# OpenTallas memory compiler (tools/mem_compiler), ASAP7 abstract view
VERSION 5.7 ;
BUSBITCHARS "[]" ;
DIVIDERCHAR "/" ;
PROPERTYDEFINITIONS
  MACRO width INTEGER ;
  MACRO depth INTEGER ;
  MACRO banks INTEGER ;
END PROPERTYDEFINITIONS
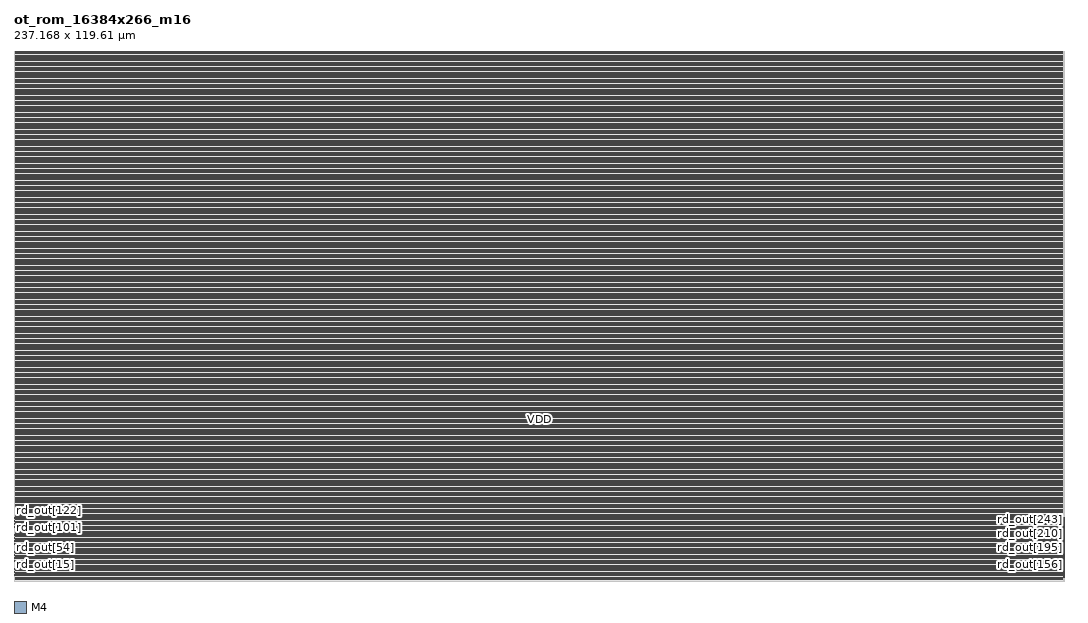
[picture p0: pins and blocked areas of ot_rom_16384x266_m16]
MACRO ot_rom_16384x266_m16
  PROPERTY width 266 ;
  PROPERTY depth 16384 ;
  PROPERTY banks 1 ;
  FOREIGN ot_rom_16384x266_m16 0 0 ;
  SYMMETRY X Y R90 ;
  SIZE 237.168 BY 119.610 ;
  CLASS BLOCK ;
  PIN clk
    DIRECTION INPUT ;
    USE CLOCK ;
    SHAPE ABUTMENT ;
    PORT
      LAYER M4 ;
      RECT 0.000 0.768 0.024 0.792 ;
    END
  END clk
  PIN ce_in
    DIRECTION INPUT ;
    USE SIGNAL ;
    SHAPE ABUTMENT ;
    PORT
      LAYER M4 ;
      RECT 0.000 0.864 0.024 0.888 ;
    END
  END ce_in
  PIN addr_in[0]
    DIRECTION INPUT ;
    USE SIGNAL ;
    SHAPE ABUTMENT ;
    PORT
      LAYER M4 ;
      RECT 0.000 0.960 0.024 0.984 ;
    END
  END addr_in[0]
  PIN addr_in[1]
    DIRECTION INPUT ;
    USE SIGNAL ;
    SHAPE ABUTMENT ;
    PORT
      LAYER M4 ;
      RECT 0.000 1.056 0.024 1.080 ;
    END
  END addr_in[1]
  PIN addr_in[2]
    DIRECTION INPUT ;
    USE SIGNAL ;
    SHAPE ABUTMENT ;
    PORT
      LAYER M4 ;
      RECT 0.000 1.152 0.024 1.176 ;
    END
  END addr_in[2]
  PIN addr_in[3]
    DIRECTION INPUT ;
    USE SIGNAL ;
    SHAPE ABUTMENT ;
    PORT
      LAYER M4 ;
      RECT 0.000 1.248 0.024 1.272 ;
    END
  END addr_in[3]
  PIN addr_in[4]
    DIRECTION INPUT ;
    USE SIGNAL ;
    SHAPE ABUTMENT ;
    PORT
      LAYER M4 ;
      RECT 0.000 1.344 0.024 1.368 ;
    END
  END addr_in[4]
  PIN addr_in[5]
    DIRECTION INPUT ;
    USE SIGNAL ;
    SHAPE ABUTMENT ;
    PORT
      LAYER M4 ;
      RECT 0.000 1.440 0.024 1.464 ;
    END
  END addr_in[5]
  PIN addr_in[6]
    DIRECTION INPUT ;
    USE SIGNAL ;
    SHAPE ABUTMENT ;
    PORT
      LAYER M4 ;
      RECT 0.000 1.536 0.024 1.560 ;
    END
  END addr_in[6]
  PIN addr_in[7]
    DIRECTION INPUT ;
    USE SIGNAL ;
    SHAPE ABUTMENT ;
    PORT
      LAYER M4 ;
      RECT 0.000 1.632 0.024 1.656 ;
    END
  END addr_in[7]
  PIN addr_in[8]
    DIRECTION INPUT ;
    USE SIGNAL ;
    SHAPE ABUTMENT ;
    PORT
      LAYER M4 ;
      RECT 0.000 1.728 0.024 1.752 ;
    END
  END addr_in[8]
  PIN addr_in[9]
    DIRECTION INPUT ;
    USE SIGNAL ;
    SHAPE ABUTMENT ;
    PORT
      LAYER M4 ;
      RECT 0.000 1.824 0.024 1.848 ;
    END
  END addr_in[9]
  PIN addr_in[10]
    DIRECTION INPUT ;
    USE SIGNAL ;
    SHAPE ABUTMENT ;
    PORT
      LAYER M4 ;
      RECT 0.000 1.920 0.024 1.944 ;
    END
  END addr_in[10]
  PIN addr_in[11]
    DIRECTION INPUT ;
    USE SIGNAL ;
    SHAPE ABUTMENT ;
    PORT
      LAYER M4 ;
      RECT 0.000 2.016 0.024 2.040 ;
    END
  END addr_in[11]
  PIN addr_in[12]
    DIRECTION INPUT ;
    USE SIGNAL ;
    SHAPE ABUTMENT ;
    PORT
      LAYER M4 ;
      RECT 0.000 2.112 0.024 2.136 ;
    END
  END addr_in[12]
  PIN addr_in[13]
    DIRECTION INPUT ;
    USE SIGNAL ;
    SHAPE ABUTMENT ;
    PORT
      LAYER M4 ;
      RECT 0.000 2.208 0.024 2.232 ;
    END
  END addr_in[13]
  PIN rd_out[0]
    DIRECTION OUTPUT ;
    USE SIGNAL ;
    SHAPE ABUTMENT ;
    PORT
      LAYER M4 ;
      RECT 0.000 2.304 0.024 2.328 ;
    END
  END rd_out[0]
  PIN rd_out[1]
    DIRECTION OUTPUT ;
    USE SIGNAL ;
    SHAPE ABUTMENT ;
    PORT
      LAYER M4 ;
      RECT 0.000 2.400 0.024 2.424 ;
    END
  END rd_out[1]
  PIN rd_out[2]
    DIRECTION OUTPUT ;
    USE SIGNAL ;
    SHAPE ABUTMENT ;
    PORT
      LAYER M4 ;
      RECT 0.000 2.496 0.024 2.520 ;
    END
  END rd_out[2]
  PIN rd_out[3]
    DIRECTION OUTPUT ;
    USE SIGNAL ;
    SHAPE ABUTMENT ;
    PORT
      LAYER M4 ;
      RECT 0.000 2.592 0.024 2.616 ;
    END
  END rd_out[3]
  PIN rd_out[4]
    DIRECTION OUTPUT ;
    USE SIGNAL ;
    SHAPE ABUTMENT ;
    PORT
      LAYER M4 ;
      RECT 0.000 2.688 0.024 2.712 ;
    END
  END rd_out[4]
  PIN rd_out[5]
    DIRECTION OUTPUT ;
    USE SIGNAL ;
    SHAPE ABUTMENT ;
    PORT
      LAYER M4 ;
      RECT 0.000 2.784 0.024 2.808 ;
    END
  END rd_out[5]
  PIN rd_out[6]
    DIRECTION OUTPUT ;
    USE SIGNAL ;
    SHAPE ABUTMENT ;
    PORT
      LAYER M4 ;
      RECT 0.000 2.880 0.024 2.904 ;
    END
  END rd_out[6]
  PIN rd_out[7]
    DIRECTION OUTPUT ;
    USE SIGNAL ;
    SHAPE ABUTMENT ;
    PORT
      LAYER M4 ;
      RECT 0.000 2.976 0.024 3.000 ;
    END
  END rd_out[7]
  PIN rd_out[8]
    DIRECTION OUTPUT ;
    USE SIGNAL ;
    SHAPE ABUTMENT ;
    PORT
      LAYER M4 ;
      RECT 0.000 3.072 0.024 3.096 ;
    END
  END rd_out[8]
  PIN rd_out[9]
    DIRECTION OUTPUT ;
    USE SIGNAL ;
    SHAPE ABUTMENT ;
    PORT
      LAYER M4 ;
      RECT 0.000 3.168 0.024 3.192 ;
    END
  END rd_out[9]
  PIN rd_out[10]
    DIRECTION OUTPUT ;
    USE SIGNAL ;
    SHAPE ABUTMENT ;
    PORT
      LAYER M4 ;
      RECT 0.000 3.264 0.024 3.288 ;
    END
  END rd_out[10]
  PIN rd_out[11]
    DIRECTION OUTPUT ;
    USE SIGNAL ;
    SHAPE ABUTMENT ;
    PORT
      LAYER M4 ;
      RECT 0.000 3.360 0.024 3.384 ;
    END
  END rd_out[11]
  PIN rd_out[12]
    DIRECTION OUTPUT ;
    USE SIGNAL ;
    SHAPE ABUTMENT ;
    PORT
      LAYER M4 ;
      RECT 0.000 3.456 0.024 3.480 ;
    END
  END rd_out[12]
  PIN rd_out[13]
    DIRECTION OUTPUT ;
    USE SIGNAL ;
    SHAPE ABUTMENT ;
    PORT
      LAYER M4 ;
      RECT 0.000 3.552 0.024 3.576 ;
    END
  END rd_out[13]
  PIN rd_out[14]
    DIRECTION OUTPUT ;
    USE SIGNAL ;
    SHAPE ABUTMENT ;
    PORT
      LAYER M4 ;
      RECT 0.000 3.648 0.024 3.672 ;
    END
  END rd_out[14]
  PIN rd_out[15]
    DIRECTION OUTPUT ;
    USE SIGNAL ;
    SHAPE ABUTMENT ;
    PORT
      LAYER M4 ;
      RECT 0.000 3.744 0.024 3.768 ;
    END
  END rd_out[15]
  PIN rd_out[16]
    DIRECTION OUTPUT ;
    USE SIGNAL ;
    SHAPE ABUTMENT ;
    PORT
      LAYER M4 ;
      RECT 0.000 3.840 0.024 3.864 ;
    END
  END rd_out[16]
  PIN rd_out[17]
    DIRECTION OUTPUT ;
    USE SIGNAL ;
    SHAPE ABUTMENT ;
    PORT
      LAYER M4 ;
      RECT 0.000 3.936 0.024 3.960 ;
    END
  END rd_out[17]
  PIN rd_out[18]
    DIRECTION OUTPUT ;
    USE SIGNAL ;
    SHAPE ABUTMENT ;
    PORT
      LAYER M4 ;
      RECT 0.000 4.032 0.024 4.056 ;
    END
  END rd_out[18]
  PIN rd_out[19]
    DIRECTION OUTPUT ;
    USE SIGNAL ;
    SHAPE ABUTMENT ;
    PORT
      LAYER M4 ;
      RECT 0.000 4.128 0.024 4.152 ;
    END
  END rd_out[19]
  PIN rd_out[20]
    DIRECTION OUTPUT ;
    USE SIGNAL ;
    SHAPE ABUTMENT ;
    PORT
      LAYER M4 ;
      RECT 0.000 4.224 0.024 4.248 ;
    END
  END rd_out[20]
  PIN rd_out[21]
    DIRECTION OUTPUT ;
    USE SIGNAL ;
    SHAPE ABUTMENT ;
    PORT
      LAYER M4 ;
      RECT 0.000 4.320 0.024 4.344 ;
    END
  END rd_out[21]
  PIN rd_out[22]
    DIRECTION OUTPUT ;
    USE SIGNAL ;
    SHAPE ABUTMENT ;
    PORT
      LAYER M4 ;
      RECT 0.000 4.416 0.024 4.440 ;
    END
  END rd_out[22]
  PIN rd_out[23]
    DIRECTION OUTPUT ;
    USE SIGNAL ;
    SHAPE ABUTMENT ;
    PORT
      LAYER M4 ;
      RECT 0.000 4.512 0.024 4.536 ;
    END
  END rd_out[23]
  PIN rd_out[24]
    DIRECTION OUTPUT ;
    USE SIGNAL ;
    SHAPE ABUTMENT ;
    PORT
      LAYER M4 ;
      RECT 0.000 4.608 0.024 4.632 ;
    END
  END rd_out[24]
  PIN rd_out[25]
    DIRECTION OUTPUT ;
    USE SIGNAL ;
    SHAPE ABUTMENT ;
    PORT
      LAYER M4 ;
      RECT 0.000 4.704 0.024 4.728 ;
    END
  END rd_out[25]
  PIN rd_out[26]
    DIRECTION OUTPUT ;
    USE SIGNAL ;
    SHAPE ABUTMENT ;
    PORT
      LAYER M4 ;
      RECT 0.000 4.800 0.024 4.824 ;
    END
  END rd_out[26]
  PIN rd_out[27]
    DIRECTION OUTPUT ;
    USE SIGNAL ;
    SHAPE ABUTMENT ;
    PORT
      LAYER M4 ;
      RECT 0.000 4.896 0.024 4.920 ;
    END
  END rd_out[27]
  PIN rd_out[28]
    DIRECTION OUTPUT ;
    USE SIGNAL ;
    SHAPE ABUTMENT ;
    PORT
      LAYER M4 ;
      RECT 0.000 4.992 0.024 5.016 ;
    END
  END rd_out[28]
  PIN rd_out[29]
    DIRECTION OUTPUT ;
    USE SIGNAL ;
    SHAPE ABUTMENT ;
    PORT
      LAYER M4 ;
      RECT 0.000 5.088 0.024 5.112 ;
    END
  END rd_out[29]
  PIN rd_out[30]
    DIRECTION OUTPUT ;
    USE SIGNAL ;
    SHAPE ABUTMENT ;
    PORT
      LAYER M4 ;
      RECT 0.000 5.184 0.024 5.208 ;
    END
  END rd_out[30]
  PIN rd_out[31]
    DIRECTION OUTPUT ;
    USE SIGNAL ;
    SHAPE ABUTMENT ;
    PORT
      LAYER M4 ;
      RECT 0.000 5.280 0.024 5.304 ;
    END
  END rd_out[31]
  PIN rd_out[32]
    DIRECTION OUTPUT ;
    USE SIGNAL ;
    SHAPE ABUTMENT ;
    PORT
      LAYER M4 ;
      RECT 0.000 5.376 0.024 5.400 ;
    END
  END rd_out[32]
  PIN rd_out[33]
    DIRECTION OUTPUT ;
    USE SIGNAL ;
    SHAPE ABUTMENT ;
    PORT
      LAYER M4 ;
      RECT 0.000 5.472 0.024 5.496 ;
    END
  END rd_out[33]
  PIN rd_out[34]
    DIRECTION OUTPUT ;
    USE SIGNAL ;
    SHAPE ABUTMENT ;
    PORT
      LAYER M4 ;
      RECT 0.000 5.568 0.024 5.592 ;
    END
  END rd_out[34]
  PIN rd_out[35]
    DIRECTION OUTPUT ;
    USE SIGNAL ;
    SHAPE ABUTMENT ;
    PORT
      LAYER M4 ;
      RECT 0.000 5.664 0.024 5.688 ;
    END
  END rd_out[35]
  PIN rd_out[36]
    DIRECTION OUTPUT ;
    USE SIGNAL ;
    SHAPE ABUTMENT ;
    PORT
      LAYER M4 ;
      RECT 0.000 5.760 0.024 5.784 ;
    END
  END rd_out[36]
  PIN rd_out[37]
    DIRECTION OUTPUT ;
    USE SIGNAL ;
    SHAPE ABUTMENT ;
    PORT
      LAYER M4 ;
      RECT 0.000 5.856 0.024 5.880 ;
    END
  END rd_out[37]
  PIN rd_out[38]
    DIRECTION OUTPUT ;
    USE SIGNAL ;
    SHAPE ABUTMENT ;
    PORT
      LAYER M4 ;
      RECT 0.000 5.952 0.024 5.976 ;
    END
  END rd_out[38]
  PIN rd_out[39]
    DIRECTION OUTPUT ;
    USE SIGNAL ;
    SHAPE ABUTMENT ;
    PORT
      LAYER M4 ;
      RECT 0.000 6.048 0.024 6.072 ;
    END
  END rd_out[39]
  PIN rd_out[40]
    DIRECTION OUTPUT ;
    USE SIGNAL ;
    SHAPE ABUTMENT ;
    PORT
      LAYER M4 ;
      RECT 0.000 6.144 0.024 6.168 ;
    END
  END rd_out[40]
  PIN rd_out[41]
    DIRECTION OUTPUT ;
    USE SIGNAL ;
    SHAPE ABUTMENT ;
    PORT
      LAYER M4 ;
      RECT 0.000 6.240 0.024 6.264 ;
    END
  END rd_out[41]
  PIN rd_out[42]
    DIRECTION OUTPUT ;
    USE SIGNAL ;
    SHAPE ABUTMENT ;
    PORT
      LAYER M4 ;
      RECT 0.000 6.336 0.024 6.360 ;
    END
  END rd_out[42]
  PIN rd_out[43]
    DIRECTION OUTPUT ;
    USE SIGNAL ;
    SHAPE ABUTMENT ;
    PORT
      LAYER M4 ;
      RECT 0.000 6.432 0.024 6.456 ;
    END
  END rd_out[43]
  PIN rd_out[44]
    DIRECTION OUTPUT ;
    USE SIGNAL ;
    SHAPE ABUTMENT ;
    PORT
      LAYER M4 ;
      RECT 0.000 6.528 0.024 6.552 ;
    END
  END rd_out[44]
  PIN rd_out[45]
    DIRECTION OUTPUT ;
    USE SIGNAL ;
    SHAPE ABUTMENT ;
    PORT
      LAYER M4 ;
      RECT 0.000 6.624 0.024 6.648 ;
    END
  END rd_out[45]
  PIN rd_out[46]
    DIRECTION OUTPUT ;
    USE SIGNAL ;
    SHAPE ABUTMENT ;
    PORT
      LAYER M4 ;
      RECT 0.000 6.720 0.024 6.744 ;
    END
  END rd_out[46]
  PIN rd_out[47]
    DIRECTION OUTPUT ;
    USE SIGNAL ;
    SHAPE ABUTMENT ;
    PORT
      LAYER M4 ;
      RECT 0.000 6.816 0.024 6.840 ;
    END
  END rd_out[47]
  PIN rd_out[48]
    DIRECTION OUTPUT ;
    USE SIGNAL ;
    SHAPE ABUTMENT ;
    PORT
      LAYER M4 ;
      RECT 0.000 6.912 0.024 6.936 ;
    END
  END rd_out[48]
  PIN rd_out[49]
    DIRECTION OUTPUT ;
    USE SIGNAL ;
    SHAPE ABUTMENT ;
    PORT
      LAYER M4 ;
      RECT 0.000 7.008 0.024 7.032 ;
    END
  END rd_out[49]
  PIN rd_out[50]
    DIRECTION OUTPUT ;
    USE SIGNAL ;
    SHAPE ABUTMENT ;
    PORT
      LAYER M4 ;
      RECT 0.000 7.104 0.024 7.128 ;
    END
  END rd_out[50]
  PIN rd_out[51]
    DIRECTION OUTPUT ;
    USE SIGNAL ;
    SHAPE ABUTMENT ;
    PORT
      LAYER M4 ;
      RECT 0.000 7.200 0.024 7.224 ;
    END
  END rd_out[51]
  PIN rd_out[52]
    DIRECTION OUTPUT ;
    USE SIGNAL ;
    SHAPE ABUTMENT ;
    PORT
      LAYER M4 ;
      RECT 0.000 7.296 0.024 7.320 ;
    END
  END rd_out[52]
  PIN rd_out[53]
    DIRECTION OUTPUT ;
    USE SIGNAL ;
    SHAPE ABUTMENT ;
    PORT
      LAYER M4 ;
      RECT 0.000 7.392 0.024 7.416 ;
    END
  END rd_out[53]
  PIN rd_out[54]
    DIRECTION OUTPUT ;
    USE SIGNAL ;
    SHAPE ABUTMENT ;
    PORT
      LAYER M4 ;
      RECT 0.000 7.488 0.024 7.512 ;
    END
  END rd_out[54]
  PIN rd_out[55]
    DIRECTION OUTPUT ;
    USE SIGNAL ;
    SHAPE ABUTMENT ;
    PORT
      LAYER M4 ;
      RECT 0.000 7.584 0.024 7.608 ;
    END
  END rd_out[55]
  PIN rd_out[56]
    DIRECTION OUTPUT ;
    USE SIGNAL ;
    SHAPE ABUTMENT ;
    PORT
      LAYER M4 ;
      RECT 0.000 7.680 0.024 7.704 ;
    END
  END rd_out[56]
  PIN rd_out[57]
    DIRECTION OUTPUT ;
    USE SIGNAL ;
    SHAPE ABUTMENT ;
    PORT
      LAYER M4 ;
      RECT 0.000 7.776 0.024 7.800 ;
    END
  END rd_out[57]
  PIN rd_out[58]
    DIRECTION OUTPUT ;
    USE SIGNAL ;
    SHAPE ABUTMENT ;
    PORT
      LAYER M4 ;
      RECT 0.000 7.872 0.024 7.896 ;
    END
  END rd_out[58]
  PIN rd_out[59]
    DIRECTION OUTPUT ;
    USE SIGNAL ;
    SHAPE ABUTMENT ;
    PORT
      LAYER M4 ;
      RECT 0.000 7.968 0.024 7.992 ;
    END
  END rd_out[59]
  PIN rd_out[60]
    DIRECTION OUTPUT ;
    USE SIGNAL ;
    SHAPE ABUTMENT ;
    PORT
      LAYER M4 ;
      RECT 0.000 8.064 0.024 8.088 ;
    END
  END rd_out[60]
  PIN rd_out[61]
    DIRECTION OUTPUT ;
    USE SIGNAL ;
    SHAPE ABUTMENT ;
    PORT
      LAYER M4 ;
      RECT 0.000 8.160 0.024 8.184 ;
    END
  END rd_out[61]
  PIN rd_out[62]
    DIRECTION OUTPUT ;
    USE SIGNAL ;
    SHAPE ABUTMENT ;
    PORT
      LAYER M4 ;
      RECT 0.000 8.256 0.024 8.280 ;
    END
  END rd_out[62]
  PIN rd_out[63]
    DIRECTION OUTPUT ;
    USE SIGNAL ;
    SHAPE ABUTMENT ;
    PORT
      LAYER M4 ;
      RECT 0.000 8.352 0.024 8.376 ;
    END
  END rd_out[63]
  PIN rd_out[64]
    DIRECTION OUTPUT ;
    USE SIGNAL ;
    SHAPE ABUTMENT ;
    PORT
      LAYER M4 ;
      RECT 0.000 8.448 0.024 8.472 ;
    END
  END rd_out[64]
  PIN rd_out[65]
    DIRECTION OUTPUT ;
    USE SIGNAL ;
    SHAPE ABUTMENT ;
    PORT
      LAYER M4 ;
      RECT 0.000 8.544 0.024 8.568 ;
    END
  END rd_out[65]
  PIN rd_out[66]
    DIRECTION OUTPUT ;
    USE SIGNAL ;
    SHAPE ABUTMENT ;
    PORT
      LAYER M4 ;
      RECT 0.000 8.640 0.024 8.664 ;
    END
  END rd_out[66]
  PIN rd_out[67]
    DIRECTION OUTPUT ;
    USE SIGNAL ;
    SHAPE ABUTMENT ;
    PORT
      LAYER M4 ;
      RECT 0.000 8.736 0.024 8.760 ;
    END
  END rd_out[67]
  PIN rd_out[68]
    DIRECTION OUTPUT ;
    USE SIGNAL ;
    SHAPE ABUTMENT ;
    PORT
      LAYER M4 ;
      RECT 0.000 8.832 0.024 8.856 ;
    END
  END rd_out[68]
  PIN rd_out[69]
    DIRECTION OUTPUT ;
    USE SIGNAL ;
    SHAPE ABUTMENT ;
    PORT
      LAYER M4 ;
      RECT 0.000 8.928 0.024 8.952 ;
    END
  END rd_out[69]
  PIN rd_out[70]
    DIRECTION OUTPUT ;
    USE SIGNAL ;
    SHAPE ABUTMENT ;
    PORT
      LAYER M4 ;
      RECT 0.000 9.024 0.024 9.048 ;
    END
  END rd_out[70]
  PIN rd_out[71]
    DIRECTION OUTPUT ;
    USE SIGNAL ;
    SHAPE ABUTMENT ;
    PORT
      LAYER M4 ;
      RECT 0.000 9.120 0.024 9.144 ;
    END
  END rd_out[71]
  PIN rd_out[72]
    DIRECTION OUTPUT ;
    USE SIGNAL ;
    SHAPE ABUTMENT ;
    PORT
      LAYER M4 ;
      RECT 0.000 9.216 0.024 9.240 ;
    END
  END rd_out[72]
  PIN rd_out[73]
    DIRECTION OUTPUT ;
    USE SIGNAL ;
    SHAPE ABUTMENT ;
    PORT
      LAYER M4 ;
      RECT 0.000 9.312 0.024 9.336 ;
    END
  END rd_out[73]
  PIN rd_out[74]
    DIRECTION OUTPUT ;
    USE SIGNAL ;
    SHAPE ABUTMENT ;
    PORT
      LAYER M4 ;
      RECT 0.000 9.408 0.024 9.432 ;
    END
  END rd_out[74]
  PIN rd_out[75]
    DIRECTION OUTPUT ;
    USE SIGNAL ;
    SHAPE ABUTMENT ;
    PORT
      LAYER M4 ;
      RECT 0.000 9.504 0.024 9.528 ;
    END
  END rd_out[75]
  PIN rd_out[76]
    DIRECTION OUTPUT ;
    USE SIGNAL ;
    SHAPE ABUTMENT ;
    PORT
      LAYER M4 ;
      RECT 0.000 9.600 0.024 9.624 ;
    END
  END rd_out[76]
  PIN rd_out[77]
    DIRECTION OUTPUT ;
    USE SIGNAL ;
    SHAPE ABUTMENT ;
    PORT
      LAYER M4 ;
      RECT 0.000 9.696 0.024 9.720 ;
    END
  END rd_out[77]
  PIN rd_out[78]
    DIRECTION OUTPUT ;
    USE SIGNAL ;
    SHAPE ABUTMENT ;
    PORT
      LAYER M4 ;
      RECT 0.000 9.792 0.024 9.816 ;
    END
  END rd_out[78]
  PIN rd_out[79]
    DIRECTION OUTPUT ;
    USE SIGNAL ;
    SHAPE ABUTMENT ;
    PORT
      LAYER M4 ;
      RECT 0.000 9.888 0.024 9.912 ;
    END
  END rd_out[79]
  PIN rd_out[80]
    DIRECTION OUTPUT ;
    USE SIGNAL ;
    SHAPE ABUTMENT ;
    PORT
      LAYER M4 ;
      RECT 0.000 9.984 0.024 10.008 ;
    END
  END rd_out[80]
  PIN rd_out[81]
    DIRECTION OUTPUT ;
    USE SIGNAL ;
    SHAPE ABUTMENT ;
    PORT
      LAYER M4 ;
      RECT 0.000 10.080 0.024 10.104 ;
    END
  END rd_out[81]
  PIN rd_out[82]
    DIRECTION OUTPUT ;
    USE SIGNAL ;
    SHAPE ABUTMENT ;
    PORT
      LAYER M4 ;
      RECT 0.000 10.176 0.024 10.200 ;
    END
  END rd_out[82]
  PIN rd_out[83]
    DIRECTION OUTPUT ;
    USE SIGNAL ;
    SHAPE ABUTMENT ;
    PORT
      LAYER M4 ;
      RECT 0.000 10.272 0.024 10.296 ;
    END
  END rd_out[83]
  PIN rd_out[84]
    DIRECTION OUTPUT ;
    USE SIGNAL ;
    SHAPE ABUTMENT ;
    PORT
      LAYER M4 ;
      RECT 0.000 10.368 0.024 10.392 ;
    END
  END rd_out[84]
  PIN rd_out[85]
    DIRECTION OUTPUT ;
    USE SIGNAL ;
    SHAPE ABUTMENT ;
    PORT
      LAYER M4 ;
      RECT 0.000 10.464 0.024 10.488 ;
    END
  END rd_out[85]
  PIN rd_out[86]
    DIRECTION OUTPUT ;
    USE SIGNAL ;
    SHAPE ABUTMENT ;
    PORT
      LAYER M4 ;
      RECT 0.000 10.560 0.024 10.584 ;
    END
  END rd_out[86]
  PIN rd_out[87]
    DIRECTION OUTPUT ;
    USE SIGNAL ;
    SHAPE ABUTMENT ;
    PORT
      LAYER M4 ;
      RECT 0.000 10.656 0.024 10.680 ;
    END
  END rd_out[87]
  PIN rd_out[88]
    DIRECTION OUTPUT ;
    USE SIGNAL ;
    SHAPE ABUTMENT ;
    PORT
      LAYER M4 ;
      RECT 0.000 10.752 0.024 10.776 ;
    END
  END rd_out[88]
  PIN rd_out[89]
    DIRECTION OUTPUT ;
    USE SIGNAL ;
    SHAPE ABUTMENT ;
    PORT
      LAYER M4 ;
      RECT 0.000 10.848 0.024 10.872 ;
    END
  END rd_out[89]
  PIN rd_out[90]
    DIRECTION OUTPUT ;
    USE SIGNAL ;
    SHAPE ABUTMENT ;
    PORT
      LAYER M4 ;
      RECT 0.000 10.944 0.024 10.968 ;
    END
  END rd_out[90]
  PIN rd_out[91]
    DIRECTION OUTPUT ;
    USE SIGNAL ;
    SHAPE ABUTMENT ;
    PORT
      LAYER M4 ;
      RECT 0.000 11.040 0.024 11.064 ;
    END
  END rd_out[91]
  PIN rd_out[92]
    DIRECTION OUTPUT ;
    USE SIGNAL ;
    SHAPE ABUTMENT ;
    PORT
      LAYER M4 ;
      RECT 0.000 11.136 0.024 11.160 ;
    END
  END rd_out[92]
  PIN rd_out[93]
    DIRECTION OUTPUT ;
    USE SIGNAL ;
    SHAPE ABUTMENT ;
    PORT
      LAYER M4 ;
      RECT 0.000 11.232 0.024 11.256 ;
    END
  END rd_out[93]
  PIN rd_out[94]
    DIRECTION OUTPUT ;
    USE SIGNAL ;
    SHAPE ABUTMENT ;
    PORT
      LAYER M4 ;
      RECT 0.000 11.328 0.024 11.352 ;
    END
  END rd_out[94]
  PIN rd_out[95]
    DIRECTION OUTPUT ;
    USE SIGNAL ;
    SHAPE ABUTMENT ;
    PORT
      LAYER M4 ;
      RECT 0.000 11.424 0.024 11.448 ;
    END
  END rd_out[95]
  PIN rd_out[96]
    DIRECTION OUTPUT ;
    USE SIGNAL ;
    SHAPE ABUTMENT ;
    PORT
      LAYER M4 ;
      RECT 0.000 11.520 0.024 11.544 ;
    END
  END rd_out[96]
  PIN rd_out[97]
    DIRECTION OUTPUT ;
    USE SIGNAL ;
    SHAPE ABUTMENT ;
    PORT
      LAYER M4 ;
      RECT 0.000 11.616 0.024 11.640 ;
    END
  END rd_out[97]
  PIN rd_out[98]
    DIRECTION OUTPUT ;
    USE SIGNAL ;
    SHAPE ABUTMENT ;
    PORT
      LAYER M4 ;
      RECT 0.000 11.712 0.024 11.736 ;
    END
  END rd_out[98]
  PIN rd_out[99]
    DIRECTION OUTPUT ;
    USE SIGNAL ;
    SHAPE ABUTMENT ;
    PORT
      LAYER M4 ;
      RECT 0.000 11.808 0.024 11.832 ;
    END
  END rd_out[99]
  PIN rd_out[100]
    DIRECTION OUTPUT ;
    USE SIGNAL ;
    SHAPE ABUTMENT ;
    PORT
      LAYER M4 ;
      RECT 0.000 11.904 0.024 11.928 ;
    END
  END rd_out[100]
  PIN rd_out[101]
    DIRECTION OUTPUT ;
    USE SIGNAL ;
    SHAPE ABUTMENT ;
    PORT
      LAYER M4 ;
      RECT 0.000 12.000 0.024 12.024 ;
    END
  END rd_out[101]
  PIN rd_out[102]
    DIRECTION OUTPUT ;
    USE SIGNAL ;
    SHAPE ABUTMENT ;
    PORT
      LAYER M4 ;
      RECT 0.000 12.096 0.024 12.120 ;
    END
  END rd_out[102]
  PIN rd_out[103]
    DIRECTION OUTPUT ;
    USE SIGNAL ;
    SHAPE ABUTMENT ;
    PORT
      LAYER M4 ;
      RECT 0.000 12.192 0.024 12.216 ;
    END
  END rd_out[103]
  PIN rd_out[104]
    DIRECTION OUTPUT ;
    USE SIGNAL ;
    SHAPE ABUTMENT ;
    PORT
      LAYER M4 ;
      RECT 0.000 12.288 0.024 12.312 ;
    END
  END rd_out[104]
  PIN rd_out[105]
    DIRECTION OUTPUT ;
    USE SIGNAL ;
    SHAPE ABUTMENT ;
    PORT
      LAYER M4 ;
      RECT 0.000 12.384 0.024 12.408 ;
    END
  END rd_out[105]
  PIN rd_out[106]
    DIRECTION OUTPUT ;
    USE SIGNAL ;
    SHAPE ABUTMENT ;
    PORT
      LAYER M4 ;
      RECT 0.000 12.480 0.024 12.504 ;
    END
  END rd_out[106]
  PIN rd_out[107]
    DIRECTION OUTPUT ;
    USE SIGNAL ;
    SHAPE ABUTMENT ;
    PORT
      LAYER M4 ;
      RECT 0.000 12.576 0.024 12.600 ;
    END
  END rd_out[107]
  PIN rd_out[108]
    DIRECTION OUTPUT ;
    USE SIGNAL ;
    SHAPE ABUTMENT ;
    PORT
      LAYER M4 ;
      RECT 0.000 12.672 0.024 12.696 ;
    END
  END rd_out[108]
  PIN rd_out[109]
    DIRECTION OUTPUT ;
    USE SIGNAL ;
    SHAPE ABUTMENT ;
    PORT
      LAYER M4 ;
      RECT 0.000 12.768 0.024 12.792 ;
    END
  END rd_out[109]
  PIN rd_out[110]
    DIRECTION OUTPUT ;
    USE SIGNAL ;
    SHAPE ABUTMENT ;
    PORT
      LAYER M4 ;
      RECT 0.000 12.864 0.024 12.888 ;
    END
  END rd_out[110]
  PIN rd_out[111]
    DIRECTION OUTPUT ;
    USE SIGNAL ;
    SHAPE ABUTMENT ;
    PORT
      LAYER M4 ;
      RECT 0.000 12.960 0.024 12.984 ;
    END
  END rd_out[111]
  PIN rd_out[112]
    DIRECTION OUTPUT ;
    USE SIGNAL ;
    SHAPE ABUTMENT ;
    PORT
      LAYER M4 ;
      RECT 0.000 13.056 0.024 13.080 ;
    END
  END rd_out[112]
  PIN rd_out[113]
    DIRECTION OUTPUT ;
    USE SIGNAL ;
    SHAPE ABUTMENT ;
    PORT
      LAYER M4 ;
      RECT 0.000 13.152 0.024 13.176 ;
    END
  END rd_out[113]
  PIN rd_out[114]
    DIRECTION OUTPUT ;
    USE SIGNAL ;
    SHAPE ABUTMENT ;
    PORT
      LAYER M4 ;
      RECT 0.000 13.248 0.024 13.272 ;
    END
  END rd_out[114]
  PIN rd_out[115]
    DIRECTION OUTPUT ;
    USE SIGNAL ;
    SHAPE ABUTMENT ;
    PORT
      LAYER M4 ;
      RECT 0.000 13.344 0.024 13.368 ;
    END
  END rd_out[115]
  PIN rd_out[116]
    DIRECTION OUTPUT ;
    USE SIGNAL ;
    SHAPE ABUTMENT ;
    PORT
      LAYER M4 ;
      RECT 0.000 13.440 0.024 13.464 ;
    END
  END rd_out[116]
  PIN rd_out[117]
    DIRECTION OUTPUT ;
    USE SIGNAL ;
    SHAPE ABUTMENT ;
    PORT
      LAYER M4 ;
      RECT 0.000 13.536 0.024 13.560 ;
    END
  END rd_out[117]
  PIN rd_out[118]
    DIRECTION OUTPUT ;
    USE SIGNAL ;
    SHAPE ABUTMENT ;
    PORT
      LAYER M4 ;
      RECT 0.000 13.632 0.024 13.656 ;
    END
  END rd_out[118]
  PIN rd_out[119]
    DIRECTION OUTPUT ;
    USE SIGNAL ;
    SHAPE ABUTMENT ;
    PORT
      LAYER M4 ;
      RECT 0.000 13.728 0.024 13.752 ;
    END
  END rd_out[119]
  PIN rd_out[120]
    DIRECTION OUTPUT ;
    USE SIGNAL ;
    SHAPE ABUTMENT ;
    PORT
      LAYER M4 ;
      RECT 0.000 13.824 0.024 13.848 ;
    END
  END rd_out[120]
  PIN rd_out[121]
    DIRECTION OUTPUT ;
    USE SIGNAL ;
    SHAPE ABUTMENT ;
    PORT
      LAYER M4 ;
      RECT 0.000 13.920 0.024 13.944 ;
    END
  END rd_out[121]
  PIN rd_out[122]
    DIRECTION OUTPUT ;
    USE SIGNAL ;
    SHAPE ABUTMENT ;
    PORT
      LAYER M4 ;
      RECT 0.000 14.016 0.024 14.040 ;
    END
  END rd_out[122]
  PIN rd_out[123]
    DIRECTION OUTPUT ;
    USE SIGNAL ;
    SHAPE ABUTMENT ;
    PORT
      LAYER M4 ;
      RECT 0.000 14.112 0.024 14.136 ;
    END
  END rd_out[123]
  PIN rd_out[124]
    DIRECTION OUTPUT ;
    USE SIGNAL ;
    SHAPE ABUTMENT ;
    PORT
      LAYER M4 ;
      RECT 0.000 14.208 0.024 14.232 ;
    END
  END rd_out[124]
  PIN rd_out[125]
    DIRECTION OUTPUT ;
    USE SIGNAL ;
    SHAPE ABUTMENT ;
    PORT
      LAYER M4 ;
      RECT 237.144 0.768 237.168 0.792 ;
    END
  END rd_out[125]
  PIN rd_out[126]
    DIRECTION OUTPUT ;
    USE SIGNAL ;
    SHAPE ABUTMENT ;
    PORT
      LAYER M4 ;
      RECT 237.144 0.864 237.168 0.888 ;
    END
  END rd_out[126]
  PIN rd_out[127]
    DIRECTION OUTPUT ;
    USE SIGNAL ;
    SHAPE ABUTMENT ;
    PORT
      LAYER M4 ;
      RECT 237.144 0.960 237.168 0.984 ;
    END
  END rd_out[127]
  PIN rd_out[128]
    DIRECTION OUTPUT ;
    USE SIGNAL ;
    SHAPE ABUTMENT ;
    PORT
      LAYER M4 ;
      RECT 237.144 1.056 237.168 1.080 ;
    END
  END rd_out[128]
  PIN rd_out[129]
    DIRECTION OUTPUT ;
    USE SIGNAL ;
    SHAPE ABUTMENT ;
    PORT
      LAYER M4 ;
      RECT 237.144 1.152 237.168 1.176 ;
    END
  END rd_out[129]
  PIN rd_out[130]
    DIRECTION OUTPUT ;
    USE SIGNAL ;
    SHAPE ABUTMENT ;
    PORT
      LAYER M4 ;
      RECT 237.144 1.248 237.168 1.272 ;
    END
  END rd_out[130]
  PIN rd_out[131]
    DIRECTION OUTPUT ;
    USE SIGNAL ;
    SHAPE ABUTMENT ;
    PORT
      LAYER M4 ;
      RECT 237.144 1.344 237.168 1.368 ;
    END
  END rd_out[131]
  PIN rd_out[132]
    DIRECTION OUTPUT ;
    USE SIGNAL ;
    SHAPE ABUTMENT ;
    PORT
      LAYER M4 ;
      RECT 237.144 1.440 237.168 1.464 ;
    END
  END rd_out[132]
  PIN rd_out[133]
    DIRECTION OUTPUT ;
    USE SIGNAL ;
    SHAPE ABUTMENT ;
    PORT
      LAYER M4 ;
      RECT 237.144 1.536 237.168 1.560 ;
    END
  END rd_out[133]
  PIN rd_out[134]
    DIRECTION OUTPUT ;
    USE SIGNAL ;
    SHAPE ABUTMENT ;
    PORT
      LAYER M4 ;
      RECT 237.144 1.632 237.168 1.656 ;
    END
  END rd_out[134]
  PIN rd_out[135]
    DIRECTION OUTPUT ;
    USE SIGNAL ;
    SHAPE ABUTMENT ;
    PORT
      LAYER M4 ;
      RECT 237.144 1.728 237.168 1.752 ;
    END
  END rd_out[135]
  PIN rd_out[136]
    DIRECTION OUTPUT ;
    USE SIGNAL ;
    SHAPE ABUTMENT ;
    PORT
      LAYER M4 ;
      RECT 237.144 1.824 237.168 1.848 ;
    END
  END rd_out[136]
  PIN rd_out[137]
    DIRECTION OUTPUT ;
    USE SIGNAL ;
    SHAPE ABUTMENT ;
    PORT
      LAYER M4 ;
      RECT 237.144 1.920 237.168 1.944 ;
    END
  END rd_out[137]
  PIN rd_out[138]
    DIRECTION OUTPUT ;
    USE SIGNAL ;
    SHAPE ABUTMENT ;
    PORT
      LAYER M4 ;
      RECT 237.144 2.016 237.168 2.040 ;
    END
  END rd_out[138]
  PIN rd_out[139]
    DIRECTION OUTPUT ;
    USE SIGNAL ;
    SHAPE ABUTMENT ;
    PORT
      LAYER M4 ;
      RECT 237.144 2.112 237.168 2.136 ;
    END
  END rd_out[139]
  PIN rd_out[140]
    DIRECTION OUTPUT ;
    USE SIGNAL ;
    SHAPE ABUTMENT ;
    PORT
      LAYER M4 ;
      RECT 237.144 2.208 237.168 2.232 ;
    END
  END rd_out[140]
  PIN rd_out[141]
    DIRECTION OUTPUT ;
    USE SIGNAL ;
    SHAPE ABUTMENT ;
    PORT
      LAYER M4 ;
      RECT 237.144 2.304 237.168 2.328 ;
    END
  END rd_out[141]
  PIN rd_out[142]
    DIRECTION OUTPUT ;
    USE SIGNAL ;
    SHAPE ABUTMENT ;
    PORT
      LAYER M4 ;
      RECT 237.144 2.400 237.168 2.424 ;
    END
  END rd_out[142]
  PIN rd_out[143]
    DIRECTION OUTPUT ;
    USE SIGNAL ;
    SHAPE ABUTMENT ;
    PORT
      LAYER M4 ;
      RECT 237.144 2.496 237.168 2.520 ;
    END
  END rd_out[143]
  PIN rd_out[144]
    DIRECTION OUTPUT ;
    USE SIGNAL ;
    SHAPE ABUTMENT ;
    PORT
      LAYER M4 ;
      RECT 237.144 2.592 237.168 2.616 ;
    END
  END rd_out[144]
  PIN rd_out[145]
    DIRECTION OUTPUT ;
    USE SIGNAL ;
    SHAPE ABUTMENT ;
    PORT
      LAYER M4 ;
      RECT 237.144 2.688 237.168 2.712 ;
    END
  END rd_out[145]
  PIN rd_out[146]
    DIRECTION OUTPUT ;
    USE SIGNAL ;
    SHAPE ABUTMENT ;
    PORT
      LAYER M4 ;
      RECT 237.144 2.784 237.168 2.808 ;
    END
  END rd_out[146]
  PIN rd_out[147]
    DIRECTION OUTPUT ;
    USE SIGNAL ;
    SHAPE ABUTMENT ;
    PORT
      LAYER M4 ;
      RECT 237.144 2.880 237.168 2.904 ;
    END
  END rd_out[147]
  PIN rd_out[148]
    DIRECTION OUTPUT ;
    USE SIGNAL ;
    SHAPE ABUTMENT ;
    PORT
      LAYER M4 ;
      RECT 237.144 2.976 237.168 3.000 ;
    END
  END rd_out[148]
  PIN rd_out[149]
    DIRECTION OUTPUT ;
    USE SIGNAL ;
    SHAPE ABUTMENT ;
    PORT
      LAYER M4 ;
      RECT 237.144 3.072 237.168 3.096 ;
    END
  END rd_out[149]
  PIN rd_out[150]
    DIRECTION OUTPUT ;
    USE SIGNAL ;
    SHAPE ABUTMENT ;
    PORT
      LAYER M4 ;
      RECT 237.144 3.168 237.168 3.192 ;
    END
  END rd_out[150]
  PIN rd_out[151]
    DIRECTION OUTPUT ;
    USE SIGNAL ;
    SHAPE ABUTMENT ;
    PORT
      LAYER M4 ;
      RECT 237.144 3.264 237.168 3.288 ;
    END
  END rd_out[151]
  PIN rd_out[152]
    DIRECTION OUTPUT ;
    USE SIGNAL ;
    SHAPE ABUTMENT ;
    PORT
      LAYER M4 ;
      RECT 237.144 3.360 237.168 3.384 ;
    END
  END rd_out[152]
  PIN rd_out[153]
    DIRECTION OUTPUT ;
    USE SIGNAL ;
    SHAPE ABUTMENT ;
    PORT
      LAYER M4 ;
      RECT 237.144 3.456 237.168 3.480 ;
    END
  END rd_out[153]
  PIN rd_out[154]
    DIRECTION OUTPUT ;
    USE SIGNAL ;
    SHAPE ABUTMENT ;
    PORT
      LAYER M4 ;
      RECT 237.144 3.552 237.168 3.576 ;
    END
  END rd_out[154]
  PIN rd_out[155]
    DIRECTION OUTPUT ;
    USE SIGNAL ;
    SHAPE ABUTMENT ;
    PORT
      LAYER M4 ;
      RECT 237.144 3.648 237.168 3.672 ;
    END
  END rd_out[155]
  PIN rd_out[156]
    DIRECTION OUTPUT ;
    USE SIGNAL ;
    SHAPE ABUTMENT ;
    PORT
      LAYER M4 ;
      RECT 237.144 3.744 237.168 3.768 ;
    END
  END rd_out[156]
  PIN rd_out[157]
    DIRECTION OUTPUT ;
    USE SIGNAL ;
    SHAPE ABUTMENT ;
    PORT
      LAYER M4 ;
      RECT 237.144 3.840 237.168 3.864 ;
    END
  END rd_out[157]
  PIN rd_out[158]
    DIRECTION OUTPUT ;
    USE SIGNAL ;
    SHAPE ABUTMENT ;
    PORT
      LAYER M4 ;
      RECT 237.144 3.936 237.168 3.960 ;
    END
  END rd_out[158]
  PIN rd_out[159]
    DIRECTION OUTPUT ;
    USE SIGNAL ;
    SHAPE ABUTMENT ;
    PORT
      LAYER M4 ;
      RECT 237.144 4.032 237.168 4.056 ;
    END
  END rd_out[159]
  PIN rd_out[160]
    DIRECTION OUTPUT ;
    USE SIGNAL ;
    SHAPE ABUTMENT ;
    PORT
      LAYER M4 ;
      RECT 237.144 4.128 237.168 4.152 ;
    END
  END rd_out[160]
  PIN rd_out[161]
    DIRECTION OUTPUT ;
    USE SIGNAL ;
    SHAPE ABUTMENT ;
    PORT
      LAYER M4 ;
      RECT 237.144 4.224 237.168 4.248 ;
    END
  END rd_out[161]
  PIN rd_out[162]
    DIRECTION OUTPUT ;
    USE SIGNAL ;
    SHAPE ABUTMENT ;
    PORT
      LAYER M4 ;
      RECT 237.144 4.320 237.168 4.344 ;
    END
  END rd_out[162]
  PIN rd_out[163]
    DIRECTION OUTPUT ;
    USE SIGNAL ;
    SHAPE ABUTMENT ;
    PORT
      LAYER M4 ;
      RECT 237.144 4.416 237.168 4.440 ;
    END
  END rd_out[163]
  PIN rd_out[164]
    DIRECTION OUTPUT ;
    USE SIGNAL ;
    SHAPE ABUTMENT ;
    PORT
      LAYER M4 ;
      RECT 237.144 4.512 237.168 4.536 ;
    END
  END rd_out[164]
  PIN rd_out[165]
    DIRECTION OUTPUT ;
    USE SIGNAL ;
    SHAPE ABUTMENT ;
    PORT
      LAYER M4 ;
      RECT 237.144 4.608 237.168 4.632 ;
    END
  END rd_out[165]
  PIN rd_out[166]
    DIRECTION OUTPUT ;
    USE SIGNAL ;
    SHAPE ABUTMENT ;
    PORT
      LAYER M4 ;
      RECT 237.144 4.704 237.168 4.728 ;
    END
  END rd_out[166]
  PIN rd_out[167]
    DIRECTION OUTPUT ;
    USE SIGNAL ;
    SHAPE ABUTMENT ;
    PORT
      LAYER M4 ;
      RECT 237.144 4.800 237.168 4.824 ;
    END
  END rd_out[167]
  PIN rd_out[168]
    DIRECTION OUTPUT ;
    USE SIGNAL ;
    SHAPE ABUTMENT ;
    PORT
      LAYER M4 ;
      RECT 237.144 4.896 237.168 4.920 ;
    END
  END rd_out[168]
  PIN rd_out[169]
    DIRECTION OUTPUT ;
    USE SIGNAL ;
    SHAPE ABUTMENT ;
    PORT
      LAYER M4 ;
      RECT 237.144 4.992 237.168 5.016 ;
    END
  END rd_out[169]
  PIN rd_out[170]
    DIRECTION OUTPUT ;
    USE SIGNAL ;
    SHAPE ABUTMENT ;
    PORT
      LAYER M4 ;
      RECT 237.144 5.088 237.168 5.112 ;
    END
  END rd_out[170]
  PIN rd_out[171]
    DIRECTION OUTPUT ;
    USE SIGNAL ;
    SHAPE ABUTMENT ;
    PORT
      LAYER M4 ;
      RECT 237.144 5.184 237.168 5.208 ;
    END
  END rd_out[171]
  PIN rd_out[172]
    DIRECTION OUTPUT ;
    USE SIGNAL ;
    SHAPE ABUTMENT ;
    PORT
      LAYER M4 ;
      RECT 237.144 5.280 237.168 5.304 ;
    END
  END rd_out[172]
  PIN rd_out[173]
    DIRECTION OUTPUT ;
    USE SIGNAL ;
    SHAPE ABUTMENT ;
    PORT
      LAYER M4 ;
      RECT 237.144 5.376 237.168 5.400 ;
    END
  END rd_out[173]
  PIN rd_out[174]
    DIRECTION OUTPUT ;
    USE SIGNAL ;
    SHAPE ABUTMENT ;
    PORT
      LAYER M4 ;
      RECT 237.144 5.472 237.168 5.496 ;
    END
  END rd_out[174]
  PIN rd_out[175]
    DIRECTION OUTPUT ;
    USE SIGNAL ;
    SHAPE ABUTMENT ;
    PORT
      LAYER M4 ;
      RECT 237.144 5.568 237.168 5.592 ;
    END
  END rd_out[175]
  PIN rd_out[176]
    DIRECTION OUTPUT ;
    USE SIGNAL ;
    SHAPE ABUTMENT ;
    PORT
      LAYER M4 ;
      RECT 237.144 5.664 237.168 5.688 ;
    END
  END rd_out[176]
  PIN rd_out[177]
    DIRECTION OUTPUT ;
    USE SIGNAL ;
    SHAPE ABUTMENT ;
    PORT
      LAYER M4 ;
      RECT 237.144 5.760 237.168 5.784 ;
    END
  END rd_out[177]
  PIN rd_out[178]
    DIRECTION OUTPUT ;
    USE SIGNAL ;
    SHAPE ABUTMENT ;
    PORT
      LAYER M4 ;
      RECT 237.144 5.856 237.168 5.880 ;
    END
  END rd_out[178]
  PIN rd_out[179]
    DIRECTION OUTPUT ;
    USE SIGNAL ;
    SHAPE ABUTMENT ;
    PORT
      LAYER M4 ;
      RECT 237.144 5.952 237.168 5.976 ;
    END
  END rd_out[179]
  PIN rd_out[180]
    DIRECTION OUTPUT ;
    USE SIGNAL ;
    SHAPE ABUTMENT ;
    PORT
      LAYER M4 ;
      RECT 237.144 6.048 237.168 6.072 ;
    END
  END rd_out[180]
  PIN rd_out[181]
    DIRECTION OUTPUT ;
    USE SIGNAL ;
    SHAPE ABUTMENT ;
    PORT
      LAYER M4 ;
      RECT 237.144 6.144 237.168 6.168 ;
    END
  END rd_out[181]
  PIN rd_out[182]
    DIRECTION OUTPUT ;
    USE SIGNAL ;
    SHAPE ABUTMENT ;
    PORT
      LAYER M4 ;
      RECT 237.144 6.240 237.168 6.264 ;
    END
  END rd_out[182]
  PIN rd_out[183]
    DIRECTION OUTPUT ;
    USE SIGNAL ;
    SHAPE ABUTMENT ;
    PORT
      LAYER M4 ;
      RECT 237.144 6.336 237.168 6.360 ;
    END
  END rd_out[183]
  PIN rd_out[184]
    DIRECTION OUTPUT ;
    USE SIGNAL ;
    SHAPE ABUTMENT ;
    PORT
      LAYER M4 ;
      RECT 237.144 6.432 237.168 6.456 ;
    END
  END rd_out[184]
  PIN rd_out[185]
    DIRECTION OUTPUT ;
    USE SIGNAL ;
    SHAPE ABUTMENT ;
    PORT
      LAYER M4 ;
      RECT 237.144 6.528 237.168 6.552 ;
    END
  END rd_out[185]
  PIN rd_out[186]
    DIRECTION OUTPUT ;
    USE SIGNAL ;
    SHAPE ABUTMENT ;
    PORT
      LAYER M4 ;
      RECT 237.144 6.624 237.168 6.648 ;
    END
  END rd_out[186]
  PIN rd_out[187]
    DIRECTION OUTPUT ;
    USE SIGNAL ;
    SHAPE ABUTMENT ;
    PORT
      LAYER M4 ;
      RECT 237.144 6.720 237.168 6.744 ;
    END
  END rd_out[187]
  PIN rd_out[188]
    DIRECTION OUTPUT ;
    USE SIGNAL ;
    SHAPE ABUTMENT ;
    PORT
      LAYER M4 ;
      RECT 237.144 6.816 237.168 6.840 ;
    END
  END rd_out[188]
  PIN rd_out[189]
    DIRECTION OUTPUT ;
    USE SIGNAL ;
    SHAPE ABUTMENT ;
    PORT
      LAYER M4 ;
      RECT 237.144 6.912 237.168 6.936 ;
    END
  END rd_out[189]
  PIN rd_out[190]
    DIRECTION OUTPUT ;
    USE SIGNAL ;
    SHAPE ABUTMENT ;
    PORT
      LAYER M4 ;
      RECT 237.144 7.008 237.168 7.032 ;
    END
  END rd_out[190]
  PIN rd_out[191]
    DIRECTION OUTPUT ;
    USE SIGNAL ;
    SHAPE ABUTMENT ;
    PORT
      LAYER M4 ;
      RECT 237.144 7.104 237.168 7.128 ;
    END
  END rd_out[191]
  PIN rd_out[192]
    DIRECTION OUTPUT ;
    USE SIGNAL ;
    SHAPE ABUTMENT ;
    PORT
      LAYER M4 ;
      RECT 237.144 7.200 237.168 7.224 ;
    END
  END rd_out[192]
  PIN rd_out[193]
    DIRECTION OUTPUT ;
    USE SIGNAL ;
    SHAPE ABUTMENT ;
    PORT
      LAYER M4 ;
      RECT 237.144 7.296 237.168 7.320 ;
    END
  END rd_out[193]
  PIN rd_out[194]
    DIRECTION OUTPUT ;
    USE SIGNAL ;
    SHAPE ABUTMENT ;
    PORT
      LAYER M4 ;
      RECT 237.144 7.392 237.168 7.416 ;
    END
  END rd_out[194]
  PIN rd_out[195]
    DIRECTION OUTPUT ;
    USE SIGNAL ;
    SHAPE ABUTMENT ;
    PORT
      LAYER M4 ;
      RECT 237.144 7.488 237.168 7.512 ;
    END
  END rd_out[195]
  PIN rd_out[196]
    DIRECTION OUTPUT ;
    USE SIGNAL ;
    SHAPE ABUTMENT ;
    PORT
      LAYER M4 ;
      RECT 237.144 7.584 237.168 7.608 ;
    END
  END rd_out[196]
  PIN rd_out[197]
    DIRECTION OUTPUT ;
    USE SIGNAL ;
    SHAPE ABUTMENT ;
    PORT
      LAYER M4 ;
      RECT 237.144 7.680 237.168 7.704 ;
    END
  END rd_out[197]
  PIN rd_out[198]
    DIRECTION OUTPUT ;
    USE SIGNAL ;
    SHAPE ABUTMENT ;
    PORT
      LAYER M4 ;
      RECT 237.144 7.776 237.168 7.800 ;
    END
  END rd_out[198]
  PIN rd_out[199]
    DIRECTION OUTPUT ;
    USE SIGNAL ;
    SHAPE ABUTMENT ;
    PORT
      LAYER M4 ;
      RECT 237.144 7.872 237.168 7.896 ;
    END
  END rd_out[199]
  PIN rd_out[200]
    DIRECTION OUTPUT ;
    USE SIGNAL ;
    SHAPE ABUTMENT ;
    PORT
      LAYER M4 ;
      RECT 237.144 7.968 237.168 7.992 ;
    END
  END rd_out[200]
  PIN rd_out[201]
    DIRECTION OUTPUT ;
    USE SIGNAL ;
    SHAPE ABUTMENT ;
    PORT
      LAYER M4 ;
      RECT 237.144 8.064 237.168 8.088 ;
    END
  END rd_out[201]
  PIN rd_out[202]
    DIRECTION OUTPUT ;
    USE SIGNAL ;
    SHAPE ABUTMENT ;
    PORT
      LAYER M4 ;
      RECT 237.144 8.160 237.168 8.184 ;
    END
  END rd_out[202]
  PIN rd_out[203]
    DIRECTION OUTPUT ;
    USE SIGNAL ;
    SHAPE ABUTMENT ;
    PORT
      LAYER M4 ;
      RECT 237.144 8.256 237.168 8.280 ;
    END
  END rd_out[203]
  PIN rd_out[204]
    DIRECTION OUTPUT ;
    USE SIGNAL ;
    SHAPE ABUTMENT ;
    PORT
      LAYER M4 ;
      RECT 237.144 8.352 237.168 8.376 ;
    END
  END rd_out[204]
  PIN rd_out[205]
    DIRECTION OUTPUT ;
    USE SIGNAL ;
    SHAPE ABUTMENT ;
    PORT
      LAYER M4 ;
      RECT 237.144 8.448 237.168 8.472 ;
    END
  END rd_out[205]
  PIN rd_out[206]
    DIRECTION OUTPUT ;
    USE SIGNAL ;
    SHAPE ABUTMENT ;
    PORT
      LAYER M4 ;
      RECT 237.144 8.544 237.168 8.568 ;
    END
  END rd_out[206]
  PIN rd_out[207]
    DIRECTION OUTPUT ;
    USE SIGNAL ;
    SHAPE ABUTMENT ;
    PORT
      LAYER M4 ;
      RECT 237.144 8.640 237.168 8.664 ;
    END
  END rd_out[207]
  PIN rd_out[208]
    DIRECTION OUTPUT ;
    USE SIGNAL ;
    SHAPE ABUTMENT ;
    PORT
      LAYER M4 ;
      RECT 237.144 8.736 237.168 8.760 ;
    END
  END rd_out[208]
  PIN rd_out[209]
    DIRECTION OUTPUT ;
    USE SIGNAL ;
    SHAPE ABUTMENT ;
    PORT
      LAYER M4 ;
      RECT 237.144 8.832 237.168 8.856 ;
    END
  END rd_out[209]
  PIN rd_out[210]
    DIRECTION OUTPUT ;
    USE SIGNAL ;
    SHAPE ABUTMENT ;
    PORT
      LAYER M4 ;
      RECT 237.144 8.928 237.168 8.952 ;
    END
  END rd_out[210]
  PIN rd_out[211]
    DIRECTION OUTPUT ;
    USE SIGNAL ;
    SHAPE ABUTMENT ;
    PORT
      LAYER M4 ;
      RECT 237.144 9.024 237.168 9.048 ;
    END
  END rd_out[211]
  PIN rd_out[212]
    DIRECTION OUTPUT ;
    USE SIGNAL ;
    SHAPE ABUTMENT ;
    PORT
      LAYER M4 ;
      RECT 237.144 9.120 237.168 9.144 ;
    END
  END rd_out[212]
  PIN rd_out[213]
    DIRECTION OUTPUT ;
    USE SIGNAL ;
    SHAPE ABUTMENT ;
    PORT
      LAYER M4 ;
      RECT 237.144 9.216 237.168 9.240 ;
    END
  END rd_out[213]
  PIN rd_out[214]
    DIRECTION OUTPUT ;
    USE SIGNAL ;
    SHAPE ABUTMENT ;
    PORT
      LAYER M4 ;
      RECT 237.144 9.312 237.168 9.336 ;
    END
  END rd_out[214]
  PIN rd_out[215]
    DIRECTION OUTPUT ;
    USE SIGNAL ;
    SHAPE ABUTMENT ;
    PORT
      LAYER M4 ;
      RECT 237.144 9.408 237.168 9.432 ;
    END
  END rd_out[215]
  PIN rd_out[216]
    DIRECTION OUTPUT ;
    USE SIGNAL ;
    SHAPE ABUTMENT ;
    PORT
      LAYER M4 ;
      RECT 237.144 9.504 237.168 9.528 ;
    END
  END rd_out[216]
  PIN rd_out[217]
    DIRECTION OUTPUT ;
    USE SIGNAL ;
    SHAPE ABUTMENT ;
    PORT
      LAYER M4 ;
      RECT 237.144 9.600 237.168 9.624 ;
    END
  END rd_out[217]
  PIN rd_out[218]
    DIRECTION OUTPUT ;
    USE SIGNAL ;
    SHAPE ABUTMENT ;
    PORT
      LAYER M4 ;
      RECT 237.144 9.696 237.168 9.720 ;
    END
  END rd_out[218]
  PIN rd_out[219]
    DIRECTION OUTPUT ;
    USE SIGNAL ;
    SHAPE ABUTMENT ;
    PORT
      LAYER M4 ;
      RECT 237.144 9.792 237.168 9.816 ;
    END
  END rd_out[219]
  PIN rd_out[220]
    DIRECTION OUTPUT ;
    USE SIGNAL ;
    SHAPE ABUTMENT ;
    PORT
      LAYER M4 ;
      RECT 237.144 9.888 237.168 9.912 ;
    END
  END rd_out[220]
  PIN rd_out[221]
    DIRECTION OUTPUT ;
    USE SIGNAL ;
    SHAPE ABUTMENT ;
    PORT
      LAYER M4 ;
      RECT 237.144 9.984 237.168 10.008 ;
    END
  END rd_out[221]
  PIN rd_out[222]
    DIRECTION OUTPUT ;
    USE SIGNAL ;
    SHAPE ABUTMENT ;
    PORT
      LAYER M4 ;
      RECT 237.144 10.080 237.168 10.104 ;
    END
  END rd_out[222]
  PIN rd_out[223]
    DIRECTION OUTPUT ;
    USE SIGNAL ;
    SHAPE ABUTMENT ;
    PORT
      LAYER M4 ;
      RECT 237.144 10.176 237.168 10.200 ;
    END
  END rd_out[223]
  PIN rd_out[224]
    DIRECTION OUTPUT ;
    USE SIGNAL ;
    SHAPE ABUTMENT ;
    PORT
      LAYER M4 ;
      RECT 237.144 10.272 237.168 10.296 ;
    END
  END rd_out[224]
  PIN rd_out[225]
    DIRECTION OUTPUT ;
    USE SIGNAL ;
    SHAPE ABUTMENT ;
    PORT
      LAYER M4 ;
      RECT 237.144 10.368 237.168 10.392 ;
    END
  END rd_out[225]
  PIN rd_out[226]
    DIRECTION OUTPUT ;
    USE SIGNAL ;
    SHAPE ABUTMENT ;
    PORT
      LAYER M4 ;
      RECT 237.144 10.464 237.168 10.488 ;
    END
  END rd_out[226]
  PIN rd_out[227]
    DIRECTION OUTPUT ;
    USE SIGNAL ;
    SHAPE ABUTMENT ;
    PORT
      LAYER M4 ;
      RECT 237.144 10.560 237.168 10.584 ;
    END
  END rd_out[227]
  PIN rd_out[228]
    DIRECTION OUTPUT ;
    USE SIGNAL ;
    SHAPE ABUTMENT ;
    PORT
      LAYER M4 ;
      RECT 237.144 10.656 237.168 10.680 ;
    END
  END rd_out[228]
  PIN rd_out[229]
    DIRECTION OUTPUT ;
    USE SIGNAL ;
    SHAPE ABUTMENT ;
    PORT
      LAYER M4 ;
      RECT 237.144 10.752 237.168 10.776 ;
    END
  END rd_out[229]
  PIN rd_out[230]
    DIRECTION OUTPUT ;
    USE SIGNAL ;
    SHAPE ABUTMENT ;
    PORT
      LAYER M4 ;
      RECT 237.144 10.848 237.168 10.872 ;
    END
  END rd_out[230]
  PIN rd_out[231]
    DIRECTION OUTPUT ;
    USE SIGNAL ;
    SHAPE ABUTMENT ;
    PORT
      LAYER M4 ;
      RECT 237.144 10.944 237.168 10.968 ;
    END
  END rd_out[231]
  PIN rd_out[232]
    DIRECTION OUTPUT ;
    USE SIGNAL ;
    SHAPE ABUTMENT ;
    PORT
      LAYER M4 ;
      RECT 237.144 11.040 237.168 11.064 ;
    END
  END rd_out[232]
  PIN rd_out[233]
    DIRECTION OUTPUT ;
    USE SIGNAL ;
    SHAPE ABUTMENT ;
    PORT
      LAYER M4 ;
      RECT 237.144 11.136 237.168 11.160 ;
    END
  END rd_out[233]
  PIN rd_out[234]
    DIRECTION OUTPUT ;
    USE SIGNAL ;
    SHAPE ABUTMENT ;
    PORT
      LAYER M4 ;
      RECT 237.144 11.232 237.168 11.256 ;
    END
  END rd_out[234]
  PIN rd_out[235]
    DIRECTION OUTPUT ;
    USE SIGNAL ;
    SHAPE ABUTMENT ;
    PORT
      LAYER M4 ;
      RECT 237.144 11.328 237.168 11.352 ;
    END
  END rd_out[235]
  PIN rd_out[236]
    DIRECTION OUTPUT ;
    USE SIGNAL ;
    SHAPE ABUTMENT ;
    PORT
      LAYER M4 ;
      RECT 237.144 11.424 237.168 11.448 ;
    END
  END rd_out[236]
  PIN rd_out[237]
    DIRECTION OUTPUT ;
    USE SIGNAL ;
    SHAPE ABUTMENT ;
    PORT
      LAYER M4 ;
      RECT 237.144 11.520 237.168 11.544 ;
    END
  END rd_out[237]
  PIN rd_out[238]
    DIRECTION OUTPUT ;
    USE SIGNAL ;
    SHAPE ABUTMENT ;
    PORT
      LAYER M4 ;
      RECT 237.144 11.616 237.168 11.640 ;
    END
  END rd_out[238]
  PIN rd_out[239]
    DIRECTION OUTPUT ;
    USE SIGNAL ;
    SHAPE ABUTMENT ;
    PORT
      LAYER M4 ;
      RECT 237.144 11.712 237.168 11.736 ;
    END
  END rd_out[239]
  PIN rd_out[240]
    DIRECTION OUTPUT ;
    USE SIGNAL ;
    SHAPE ABUTMENT ;
    PORT
      LAYER M4 ;
      RECT 237.144 11.808 237.168 11.832 ;
    END
  END rd_out[240]
  PIN rd_out[241]
    DIRECTION OUTPUT ;
    USE SIGNAL ;
    SHAPE ABUTMENT ;
    PORT
      LAYER M4 ;
      RECT 237.144 11.904 237.168 11.928 ;
    END
  END rd_out[241]
  PIN rd_out[242]
    DIRECTION OUTPUT ;
    USE SIGNAL ;
    SHAPE ABUTMENT ;
    PORT
      LAYER M4 ;
      RECT 237.144 12.000 237.168 12.024 ;
    END
  END rd_out[242]
  PIN rd_out[243]
    DIRECTION OUTPUT ;
    USE SIGNAL ;
    SHAPE ABUTMENT ;
    PORT
      LAYER M4 ;
      RECT 237.144 12.096 237.168 12.120 ;
    END
  END rd_out[243]
  PIN rd_out[244]
    DIRECTION OUTPUT ;
    USE SIGNAL ;
    SHAPE ABUTMENT ;
    PORT
      LAYER M4 ;
      RECT 237.144 12.192 237.168 12.216 ;
    END
  END rd_out[244]
  PIN rd_out[245]
    DIRECTION OUTPUT ;
    USE SIGNAL ;
    SHAPE ABUTMENT ;
    PORT
      LAYER M4 ;
      RECT 237.144 12.288 237.168 12.312 ;
    END
  END rd_out[245]
  PIN rd_out[246]
    DIRECTION OUTPUT ;
    USE SIGNAL ;
    SHAPE ABUTMENT ;
    PORT
      LAYER M4 ;
      RECT 237.144 12.384 237.168 12.408 ;
    END
  END rd_out[246]
  PIN rd_out[247]
    DIRECTION OUTPUT ;
    USE SIGNAL ;
    SHAPE ABUTMENT ;
    PORT
      LAYER M4 ;
      RECT 237.144 12.480 237.168 12.504 ;
    END
  END rd_out[247]
  PIN rd_out[248]
    DIRECTION OUTPUT ;
    USE SIGNAL ;
    SHAPE ABUTMENT ;
    PORT
      LAYER M4 ;
      RECT 237.144 12.576 237.168 12.600 ;
    END
  END rd_out[248]
  PIN rd_out[249]
    DIRECTION OUTPUT ;
    USE SIGNAL ;
    SHAPE ABUTMENT ;
    PORT
      LAYER M4 ;
      RECT 237.144 12.672 237.168 12.696 ;
    END
  END rd_out[249]
  PIN rd_out[250]
    DIRECTION OUTPUT ;
    USE SIGNAL ;
    SHAPE ABUTMENT ;
    PORT
      LAYER M4 ;
      RECT 237.144 12.768 237.168 12.792 ;
    END
  END rd_out[250]
  PIN rd_out[251]
    DIRECTION OUTPUT ;
    USE SIGNAL ;
    SHAPE ABUTMENT ;
    PORT
      LAYER M4 ;
      RECT 237.144 12.864 237.168 12.888 ;
    END
  END rd_out[251]
  PIN rd_out[252]
    DIRECTION OUTPUT ;
    USE SIGNAL ;
    SHAPE ABUTMENT ;
    PORT
      LAYER M4 ;
      RECT 237.144 12.960 237.168 12.984 ;
    END
  END rd_out[252]
  PIN rd_out[253]
    DIRECTION OUTPUT ;
    USE SIGNAL ;
    SHAPE ABUTMENT ;
    PORT
      LAYER M4 ;
      RECT 237.144 13.056 237.168 13.080 ;
    END
  END rd_out[253]
  PIN rd_out[254]
    DIRECTION OUTPUT ;
    USE SIGNAL ;
    SHAPE ABUTMENT ;
    PORT
      LAYER M4 ;
      RECT 237.144 13.152 237.168 13.176 ;
    END
  END rd_out[254]
  PIN rd_out[255]
    DIRECTION OUTPUT ;
    USE SIGNAL ;
    SHAPE ABUTMENT ;
    PORT
      LAYER M4 ;
      RECT 237.144 13.248 237.168 13.272 ;
    END
  END rd_out[255]
  PIN rd_out[256]
    DIRECTION OUTPUT ;
    USE SIGNAL ;
    SHAPE ABUTMENT ;
    PORT
      LAYER M4 ;
      RECT 237.144 13.344 237.168 13.368 ;
    END
  END rd_out[256]
  PIN rd_out[257]
    DIRECTION OUTPUT ;
    USE SIGNAL ;
    SHAPE ABUTMENT ;
    PORT
      LAYER M4 ;
      RECT 237.144 13.440 237.168 13.464 ;
    END
  END rd_out[257]
  PIN rd_out[258]
    DIRECTION OUTPUT ;
    USE SIGNAL ;
    SHAPE ABUTMENT ;
    PORT
      LAYER M4 ;
      RECT 237.144 13.536 237.168 13.560 ;
    END
  END rd_out[258]
  PIN rd_out[259]
    DIRECTION OUTPUT ;
    USE SIGNAL ;
    SHAPE ABUTMENT ;
    PORT
      LAYER M4 ;
      RECT 237.144 13.632 237.168 13.656 ;
    END
  END rd_out[259]
  PIN rd_out[260]
    DIRECTION OUTPUT ;
    USE SIGNAL ;
    SHAPE ABUTMENT ;
    PORT
      LAYER M4 ;
      RECT 237.144 13.728 237.168 13.752 ;
    END
  END rd_out[260]
  PIN rd_out[261]
    DIRECTION OUTPUT ;
    USE SIGNAL ;
    SHAPE ABUTMENT ;
    PORT
      LAYER M4 ;
      RECT 237.144 13.824 237.168 13.848 ;
    END
  END rd_out[261]
  PIN rd_out[262]
    DIRECTION OUTPUT ;
    USE SIGNAL ;
    SHAPE ABUTMENT ;
    PORT
      LAYER M4 ;
      RECT 237.144 13.920 237.168 13.944 ;
    END
  END rd_out[262]
  PIN rd_out[263]
    DIRECTION OUTPUT ;
    USE SIGNAL ;
    SHAPE ABUTMENT ;
    PORT
      LAYER M4 ;
      RECT 237.144 14.016 237.168 14.040 ;
    END
  END rd_out[263]
  PIN rd_out[264]
    DIRECTION OUTPUT ;
    USE SIGNAL ;
    SHAPE ABUTMENT ;
    PORT
      LAYER M4 ;
      RECT 237.144 14.112 237.168 14.136 ;
    END
  END rd_out[264]
  PIN rd_out[265]
    DIRECTION OUTPUT ;
    USE SIGNAL ;
    SHAPE ABUTMENT ;
    PORT
      LAYER M4 ;
      RECT 237.144 14.208 237.168 14.232 ;
    END
  END rd_out[265]
  PIN VDD
    DIRECTION INOUT ;
    USE POWER ;
    PORT
      LAYER M4 ;
      RECT 0.300 0.384 236.868 0.480 ;
      RECT 0.300 1.152 236.868 1.248 ;
      RECT 0.300 1.920 236.868 2.016 ;
      RECT 0.300 2.688 236.868 2.784 ;
      RECT 0.300 3.456 236.868 3.552 ;
      RECT 0.300 4.224 236.868 4.320 ;
      RECT 0.300 4.992 236.868 5.088 ;
      RECT 0.300 5.760 236.868 5.856 ;
      RECT 0.300 6.528 236.868 6.624 ;
      RECT 0.300 7.296 236.868 7.392 ;
      RECT 0.300 8.064 236.868 8.160 ;
      RECT 0.300 8.832 236.868 8.928 ;
      RECT 0.300 9.600 236.868 9.696 ;
      RECT 0.300 10.368 236.868 10.464 ;
      RECT 0.300 11.136 236.868 11.232 ;
      RECT 0.300 11.904 236.868 12.000 ;
      RECT 0.300 12.672 236.868 12.768 ;
      RECT 0.300 13.440 236.868 13.536 ;
      RECT 0.300 14.208 236.868 14.304 ;
      RECT 0.300 14.976 236.868 15.072 ;
      RECT 0.300 15.744 236.868 15.840 ;
      RECT 0.300 16.512 236.868 16.608 ;
      RECT 0.300 17.280 236.868 17.376 ;
      RECT 0.300 18.048 236.868 18.144 ;
      RECT 0.300 18.816 236.868 18.912 ;
      RECT 0.300 19.584 236.868 19.680 ;
      RECT 0.300 20.352 236.868 20.448 ;
      RECT 0.300 21.120 236.868 21.216 ;
      RECT 0.300 21.888 236.868 21.984 ;
      RECT 0.300 22.656 236.868 22.752 ;
      RECT 0.300 23.424 236.868 23.520 ;
      RECT 0.300 24.192 236.868 24.288 ;
      RECT 0.300 24.960 236.868 25.056 ;
      RECT 0.300 25.728 236.868 25.824 ;
      RECT 0.300 26.496 236.868 26.592 ;
      RECT 0.300 27.264 236.868 27.360 ;
      RECT 0.300 28.032 236.868 28.128 ;
      RECT 0.300 28.800 236.868 28.896 ;
      RECT 0.300 29.568 236.868 29.664 ;
      RECT 0.300 30.336 236.868 30.432 ;
      RECT 0.300 31.104 236.868 31.200 ;
      RECT 0.300 31.872 236.868 31.968 ;
      RECT 0.300 32.640 236.868 32.736 ;
      RECT 0.300 33.408 236.868 33.504 ;
      RECT 0.300 34.176 236.868 34.272 ;
      RECT 0.300 34.944 236.868 35.040 ;
      RECT 0.300 35.712 236.868 35.808 ;
      RECT 0.300 36.480 236.868 36.576 ;
      RECT 0.300 37.248 236.868 37.344 ;
      RECT 0.300 38.016 236.868 38.112 ;
      RECT 0.300 38.784 236.868 38.880 ;
      RECT 0.300 39.552 236.868 39.648 ;
      RECT 0.300 40.320 236.868 40.416 ;
      RECT 0.300 41.088 236.868 41.184 ;
      RECT 0.300 41.856 236.868 41.952 ;
      RECT 0.300 42.624 236.868 42.720 ;
      RECT 0.300 43.392 236.868 43.488 ;
      RECT 0.300 44.160 236.868 44.256 ;
      RECT 0.300 44.928 236.868 45.024 ;
      RECT 0.300 45.696 236.868 45.792 ;
      RECT 0.300 46.464 236.868 46.560 ;
      RECT 0.300 47.232 236.868 47.328 ;
      RECT 0.300 48.000 236.868 48.096 ;
      RECT 0.300 48.768 236.868 48.864 ;
      RECT 0.300 49.536 236.868 49.632 ;
      RECT 0.300 50.304 236.868 50.400 ;
      RECT 0.300 51.072 236.868 51.168 ;
      RECT 0.300 51.840 236.868 51.936 ;
      RECT 0.300 52.608 236.868 52.704 ;
      RECT 0.300 53.376 236.868 53.472 ;
      RECT 0.300 54.144 236.868 54.240 ;
      RECT 0.300 54.912 236.868 55.008 ;
      RECT 0.300 55.680 236.868 55.776 ;
      RECT 0.300 56.448 236.868 56.544 ;
      RECT 0.300 57.216 236.868 57.312 ;
      RECT 0.300 57.984 236.868 58.080 ;
      RECT 0.300 58.752 236.868 58.848 ;
      RECT 0.300 59.520 236.868 59.616 ;
      RECT 0.300 60.288 236.868 60.384 ;
      RECT 0.300 61.056 236.868 61.152 ;
      RECT 0.300 61.824 236.868 61.920 ;
      RECT 0.300 62.592 236.868 62.688 ;
      RECT 0.300 63.360 236.868 63.456 ;
      RECT 0.300 64.128 236.868 64.224 ;
      RECT 0.300 64.896 236.868 64.992 ;
      RECT 0.300 65.664 236.868 65.760 ;
      RECT 0.300 66.432 236.868 66.528 ;
      RECT 0.300 67.200 236.868 67.296 ;
      RECT 0.300 67.968 236.868 68.064 ;
      RECT 0.300 68.736 236.868 68.832 ;
      RECT 0.300 69.504 236.868 69.600 ;
      RECT 0.300 70.272 236.868 70.368 ;
      RECT 0.300 71.040 236.868 71.136 ;
      RECT 0.300 71.808 236.868 71.904 ;
      RECT 0.300 72.576 236.868 72.672 ;
      RECT 0.300 73.344 236.868 73.440 ;
      RECT 0.300 74.112 236.868 74.208 ;
      RECT 0.300 74.880 236.868 74.976 ;
      RECT 0.300 75.648 236.868 75.744 ;
      RECT 0.300 76.416 236.868 76.512 ;
      RECT 0.300 77.184 236.868 77.280 ;
      RECT 0.300 77.952 236.868 78.048 ;
      RECT 0.300 78.720 236.868 78.816 ;
      RECT 0.300 79.488 236.868 79.584 ;
      RECT 0.300 80.256 236.868 80.352 ;
      RECT 0.300 81.024 236.868 81.120 ;
      RECT 0.300 81.792 236.868 81.888 ;
      RECT 0.300 82.560 236.868 82.656 ;
      RECT 0.300 83.328 236.868 83.424 ;
      RECT 0.300 84.096 236.868 84.192 ;
      RECT 0.300 84.864 236.868 84.960 ;
      RECT 0.300 85.632 236.868 85.728 ;
      RECT 0.300 86.400 236.868 86.496 ;
      RECT 0.300 87.168 236.868 87.264 ;
      RECT 0.300 87.936 236.868 88.032 ;
      RECT 0.300 88.704 236.868 88.800 ;
      RECT 0.300 89.472 236.868 89.568 ;
      RECT 0.300 90.240 236.868 90.336 ;
      RECT 0.300 91.008 236.868 91.104 ;
      RECT 0.300 91.776 236.868 91.872 ;
      RECT 0.300 92.544 236.868 92.640 ;
      RECT 0.300 93.312 236.868 93.408 ;
      RECT 0.300 94.080 236.868 94.176 ;
      RECT 0.300 94.848 236.868 94.944 ;
      RECT 0.300 95.616 236.868 95.712 ;
      RECT 0.300 96.384 236.868 96.480 ;
      RECT 0.300 97.152 236.868 97.248 ;
      RECT 0.300 97.920 236.868 98.016 ;
      RECT 0.300 98.688 236.868 98.784 ;
      RECT 0.300 99.456 236.868 99.552 ;
      RECT 0.300 100.224 236.868 100.320 ;
      RECT 0.300 100.992 236.868 101.088 ;
      RECT 0.300 101.760 236.868 101.856 ;
      RECT 0.300 102.528 236.868 102.624 ;
      RECT 0.300 103.296 236.868 103.392 ;
      RECT 0.300 104.064 236.868 104.160 ;
      RECT 0.300 104.832 236.868 104.928 ;
      RECT 0.300 105.600 236.868 105.696 ;
      RECT 0.300 106.368 236.868 106.464 ;
      RECT 0.300 107.136 236.868 107.232 ;
      RECT 0.300 107.904 236.868 108.000 ;
      RECT 0.300 108.672 236.868 108.768 ;
      RECT 0.300 109.440 236.868 109.536 ;
      RECT 0.300 110.208 236.868 110.304 ;
      RECT 0.300 110.976 236.868 111.072 ;
      RECT 0.300 111.744 236.868 111.840 ;
      RECT 0.300 112.512 236.868 112.608 ;
      RECT 0.300 113.280 236.868 113.376 ;
      RECT 0.300 114.048 236.868 114.144 ;
      RECT 0.300 114.816 236.868 114.912 ;
      RECT 0.300 115.584 236.868 115.680 ;
      RECT 0.300 116.352 236.868 116.448 ;
      RECT 0.300 117.120 236.868 117.216 ;
      RECT 0.300 117.888 236.868 117.984 ;
      RECT 0.300 118.656 236.868 118.752 ;
      RECT 0.300 119.424 236.868 119.520 ;
    END
  END VDD
  PIN VSS
    DIRECTION INOUT ;
    USE GROUND ;
    PORT
      LAYER M4 ;
      RECT 0.300 0.768 236.868 0.864 ;
      RECT 0.300 1.536 236.868 1.632 ;
      RECT 0.300 2.304 236.868 2.400 ;
      RECT 0.300 3.072 236.868 3.168 ;
      RECT 0.300 3.840 236.868 3.936 ;
      RECT 0.300 4.608 236.868 4.704 ;
      RECT 0.300 5.376 236.868 5.472 ;
      RECT 0.300 6.144 236.868 6.240 ;
      RECT 0.300 6.912 236.868 7.008 ;
      RECT 0.300 7.680 236.868 7.776 ;
      RECT 0.300 8.448 236.868 8.544 ;
      RECT 0.300 9.216 236.868 9.312 ;
      RECT 0.300 9.984 236.868 10.080 ;
      RECT 0.300 10.752 236.868 10.848 ;
      RECT 0.300 11.520 236.868 11.616 ;
      RECT 0.300 12.288 236.868 12.384 ;
      RECT 0.300 13.056 236.868 13.152 ;
      RECT 0.300 13.824 236.868 13.920 ;
      RECT 0.300 14.592 236.868 14.688 ;
      RECT 0.300 15.360 236.868 15.456 ;
      RECT 0.300 16.128 236.868 16.224 ;
      RECT 0.300 16.896 236.868 16.992 ;
      RECT 0.300 17.664 236.868 17.760 ;
      RECT 0.300 18.432 236.868 18.528 ;
      RECT 0.300 19.200 236.868 19.296 ;
      RECT 0.300 19.968 236.868 20.064 ;
      RECT 0.300 20.736 236.868 20.832 ;
      RECT 0.300 21.504 236.868 21.600 ;
      RECT 0.300 22.272 236.868 22.368 ;
      RECT 0.300 23.040 236.868 23.136 ;
      RECT 0.300 23.808 236.868 23.904 ;
      RECT 0.300 24.576 236.868 24.672 ;
      RECT 0.300 25.344 236.868 25.440 ;
      RECT 0.300 26.112 236.868 26.208 ;
      RECT 0.300 26.880 236.868 26.976 ;
      RECT 0.300 27.648 236.868 27.744 ;
      RECT 0.300 28.416 236.868 28.512 ;
      RECT 0.300 29.184 236.868 29.280 ;
      RECT 0.300 29.952 236.868 30.048 ;
      RECT 0.300 30.720 236.868 30.816 ;
      RECT 0.300 31.488 236.868 31.584 ;
      RECT 0.300 32.256 236.868 32.352 ;
      RECT 0.300 33.024 236.868 33.120 ;
      RECT 0.300 33.792 236.868 33.888 ;
      RECT 0.300 34.560 236.868 34.656 ;
      RECT 0.300 35.328 236.868 35.424 ;
      RECT 0.300 36.096 236.868 36.192 ;
      RECT 0.300 36.864 236.868 36.960 ;
      RECT 0.300 37.632 236.868 37.728 ;
      RECT 0.300 38.400 236.868 38.496 ;
      RECT 0.300 39.168 236.868 39.264 ;
      RECT 0.300 39.936 236.868 40.032 ;
      RECT 0.300 40.704 236.868 40.800 ;
      RECT 0.300 41.472 236.868 41.568 ;
      RECT 0.300 42.240 236.868 42.336 ;
      RECT 0.300 43.008 236.868 43.104 ;
      RECT 0.300 43.776 236.868 43.872 ;
      RECT 0.300 44.544 236.868 44.640 ;
      RECT 0.300 45.312 236.868 45.408 ;
      RECT 0.300 46.080 236.868 46.176 ;
      RECT 0.300 46.848 236.868 46.944 ;
      RECT 0.300 47.616 236.868 47.712 ;
      RECT 0.300 48.384 236.868 48.480 ;
      RECT 0.300 49.152 236.868 49.248 ;
      RECT 0.300 49.920 236.868 50.016 ;
      RECT 0.300 50.688 236.868 50.784 ;
      RECT 0.300 51.456 236.868 51.552 ;
      RECT 0.300 52.224 236.868 52.320 ;
      RECT 0.300 52.992 236.868 53.088 ;
      RECT 0.300 53.760 236.868 53.856 ;
      RECT 0.300 54.528 236.868 54.624 ;
      RECT 0.300 55.296 236.868 55.392 ;
      RECT 0.300 56.064 236.868 56.160 ;
      RECT 0.300 56.832 236.868 56.928 ;
      RECT 0.300 57.600 236.868 57.696 ;
      RECT 0.300 58.368 236.868 58.464 ;
      RECT 0.300 59.136 236.868 59.232 ;
      RECT 0.300 59.904 236.868 60.000 ;
      RECT 0.300 60.672 236.868 60.768 ;
      RECT 0.300 61.440 236.868 61.536 ;
      RECT 0.300 62.208 236.868 62.304 ;
      RECT 0.300 62.976 236.868 63.072 ;
      RECT 0.300 63.744 236.868 63.840 ;
      RECT 0.300 64.512 236.868 64.608 ;
      RECT 0.300 65.280 236.868 65.376 ;
      RECT 0.300 66.048 236.868 66.144 ;
      RECT 0.300 66.816 236.868 66.912 ;
      RECT 0.300 67.584 236.868 67.680 ;
      RECT 0.300 68.352 236.868 68.448 ;
      RECT 0.300 69.120 236.868 69.216 ;
      RECT 0.300 69.888 236.868 69.984 ;
      RECT 0.300 70.656 236.868 70.752 ;
      RECT 0.300 71.424 236.868 71.520 ;
      RECT 0.300 72.192 236.868 72.288 ;
      RECT 0.300 72.960 236.868 73.056 ;
      RECT 0.300 73.728 236.868 73.824 ;
      RECT 0.300 74.496 236.868 74.592 ;
      RECT 0.300 75.264 236.868 75.360 ;
      RECT 0.300 76.032 236.868 76.128 ;
      RECT 0.300 76.800 236.868 76.896 ;
      RECT 0.300 77.568 236.868 77.664 ;
      RECT 0.300 78.336 236.868 78.432 ;
      RECT 0.300 79.104 236.868 79.200 ;
      RECT 0.300 79.872 236.868 79.968 ;
      RECT 0.300 80.640 236.868 80.736 ;
      RECT 0.300 81.408 236.868 81.504 ;
      RECT 0.300 82.176 236.868 82.272 ;
      RECT 0.300 82.944 236.868 83.040 ;
      RECT 0.300 83.712 236.868 83.808 ;
      RECT 0.300 84.480 236.868 84.576 ;
      RECT 0.300 85.248 236.868 85.344 ;
      RECT 0.300 86.016 236.868 86.112 ;
      RECT 0.300 86.784 236.868 86.880 ;
      RECT 0.300 87.552 236.868 87.648 ;
      RECT 0.300 88.320 236.868 88.416 ;
      RECT 0.300 89.088 236.868 89.184 ;
      RECT 0.300 89.856 236.868 89.952 ;
      RECT 0.300 90.624 236.868 90.720 ;
      RECT 0.300 91.392 236.868 91.488 ;
      RECT 0.300 92.160 236.868 92.256 ;
      RECT 0.300 92.928 236.868 93.024 ;
      RECT 0.300 93.696 236.868 93.792 ;
      RECT 0.300 94.464 236.868 94.560 ;
      RECT 0.300 95.232 236.868 95.328 ;
      RECT 0.300 96.000 236.868 96.096 ;
      RECT 0.300 96.768 236.868 96.864 ;
      RECT 0.300 97.536 236.868 97.632 ;
      RECT 0.300 98.304 236.868 98.400 ;
      RECT 0.300 99.072 236.868 99.168 ;
      RECT 0.300 99.840 236.868 99.936 ;
      RECT 0.300 100.608 236.868 100.704 ;
      RECT 0.300 101.376 236.868 101.472 ;
      RECT 0.300 102.144 236.868 102.240 ;
      RECT 0.300 102.912 236.868 103.008 ;
      RECT 0.300 103.680 236.868 103.776 ;
      RECT 0.300 104.448 236.868 104.544 ;
      RECT 0.300 105.216 236.868 105.312 ;
      RECT 0.300 105.984 236.868 106.080 ;
      RECT 0.300 106.752 236.868 106.848 ;
      RECT 0.300 107.520 236.868 107.616 ;
      RECT 0.300 108.288 236.868 108.384 ;
      RECT 0.300 109.056 236.868 109.152 ;
      RECT 0.300 109.824 236.868 109.920 ;
      RECT 0.300 110.592 236.868 110.688 ;
      RECT 0.300 111.360 236.868 111.456 ;
      RECT 0.300 112.128 236.868 112.224 ;
      RECT 0.300 112.896 236.868 112.992 ;
      RECT 0.300 113.664 236.868 113.760 ;
      RECT 0.300 114.432 236.868 114.528 ;
      RECT 0.300 115.200 236.868 115.296 ;
      RECT 0.300 115.968 236.868 116.064 ;
      RECT 0.300 116.736 236.868 116.832 ;
      RECT 0.300 117.504 236.868 117.600 ;
      RECT 0.300 118.272 236.868 118.368 ;
      RECT 0.300 119.040 236.868 119.136 ;
    END
  END VSS
  OBS
    LAYER M1 ;
    RECT 0 0 237.168 119.610 ;
    LAYER M2 ;
    RECT 0 0 237.168 119.610 ;
    LAYER M3 ;
    RECT 0 0 237.168 119.610 ;
    LAYER M4 ;
    RECT 0.072 0 237.096 119.610 ;
  END
END ot_rom_16384x266_m16

END LIBRARY
